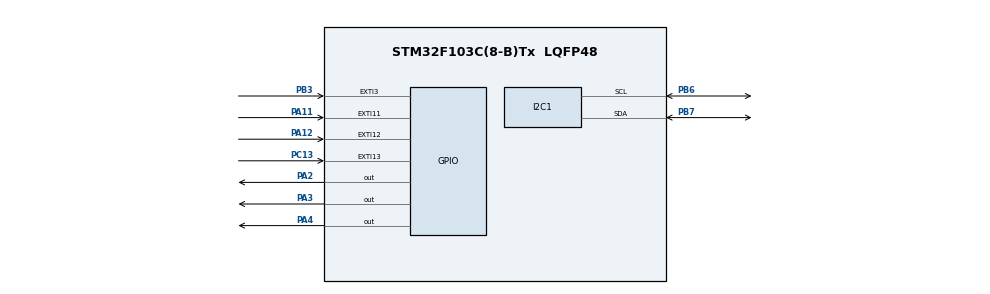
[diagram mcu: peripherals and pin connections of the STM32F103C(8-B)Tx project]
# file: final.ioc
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Mcu.Family=STM32F1
Mcu.Name=STM32F103C(8-B)Tx
Mcu.Package=LQFP48
NVIC.EXTI15_10_IRQn=true\:0\:0\:false\:false\:true\:true\:true\:true
NVIC.EXTI3_IRQn=true\:0\:0\:false\:false\:true\:true\:true\:true
NVIC.PriorityGroup=NVIC_PRIORITYGROUP_4
NVIC.TIM1_CC_IRQn=true\:0\:0\:false\:false\:true\:true\:true\:true
PA11.GPIO_ModeDefaultEXTI=GPIO_MODE_IT_RISING
PA11.Signal=GPXTI11
PA12.GPIO_ModeDefaultEXTI=GPIO_MODE_IT_FALLING
PA12.Signal=GPXTI12
PA2.Signal=GPIO_Output
PA3.Signal=GPIO_Output
PA4.Signal=GPIO_Output
PB3.GPIO_ModeDefaultEXTI=GPIO_MODE_IT_FALLING
PB3.Signal=GPXTI3
PB6.Mode=I2C
PB6.Signal=I2C1_SCL
PB7.Mode=I2C
PB7.Signal=I2C1_SDA
PC13-TAMPER-RTC.Signal=GPXTI13
ProjectManager.HeapSize=0x200
ProjectManager.StackSize=0x400
ProjectManager.TargetToolchain=STM32CubeIDE
RCC.APB1Freq_Value=8000000
RCC.APB2Freq_Value=8000000
VP_SYS_VS_ND.Mode=No_Debug
VP_TIM1_VS_ClockSourceINT.Mode=Internal
VP_TIM1_VS_ClockSourceITR.Mode=TriggerSource_ITR0
board=custom

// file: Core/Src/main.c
/* USER CODE BEGIN Header */
/**
  ******************************************************************************
  * @file           : main.c
  * @brief          : Main program body
  ******************************************************************************
  * @attention
  *
  * Copyright (c) 2023 STMicroelectronics.
  * All rights reserved.
  *
  * This software is licensed under terms that can be found in the LICENSE file
  * in the root directory of this software component.
  * If no LICENSE file comes with this software, it is provided AS-IS.
  *
  ******************************************************************************
  */
/* USER CODE END Header */
#include "main.h"
#include "button.h"
#include "CLCD_I2C.h"
#include "mpu_ss.h"

I2C_HandleTypeDef hi2c1;
CLCD_I2C_Name lcd;
TIM_HandleTypeDef htim1;

int step = -1;
double pre = 0;
int c = 0;
void SystemClock_Config(void);
static void MX_GPIO_Init(void);
static void MX_I2C1_Init(void);
static void MX_TIM1_Init(void);

int main(void)
{
  /* USER CODE BEGIN 1 */
	char buf[8];
  /* USER CODE END 1 */

  /* MCU Configuration--------------------------------------------------------*/

  /* Reset of all peripherals, Initializes the Flash interface and the Systick. */
  HAL_Init();

  /* Configure the system clock */
  SystemClock_Config();

  /* USER CODE BEGIN SysInit */
  init_button();
  /* USER CODE END SysInit */

  /* Initialize all configured peripherals */
  MX_GPIO_Init();
  MX_I2C1_Init();
  MX_TIM1_Init();
  /* USER CODE BEGIN 2 */
  MPU6050_Init(&hi2c1);
  CLCD_I2C_Init(&lcd, &hi2c1, 0x27 << 1, 16, 2);
  CLCD_I2C_Clear(&lcd);
  CLCD_I2C_CursorOn(&lcd);
  /* USER CODE END 2 */

  /* Infinite loop */
  while (1)
  {
	 CLCD_I2C_Clear(&lcd);
	 double vec = MPUgetValue(&hi2c1);
	 if(check(PIN_RESET) == 0u) {
		 step = 0;
		 CLCD_I2C_SetCursor(&lcd, 0, 0);
		 CLCD_I2C_WriteString(&lcd, "STEP: ");
		 sprintf(buf, "%d", step);
		 CLCD_I2C_WriteString(&lcd, buf);
		 HAL_Delay(200);
	 } else {
		 if(check(PIN_PAUSE) == 0u) {
			 HAL_Delay(100);
			 while(check(PIN_PAUSE) == 0u) {

			 }
		 } else {
			 if(vec - pre > 4000) {
				 step++;
			 }
		 }
	 }
	 CLCD_I2C_SetCursor(&lcd, 0, 0);
	 CLCD_I2C_WriteString(&lcd, "STEP: ");
	 sprintf(buf, "%d", vec - pre);
	 CLCD_I2C_WriteString(&lcd, buf);
	 pre = vec;
	 HAL_Delay(100);

  }
}

void SystemClock_Config(void)
{
  RCC_OscInitTypeDef RCC_OscInitStruct = {0};
  RCC_ClkInitTypeDef RCC_ClkInitStruct = {0};

  /** Initializes the RCC Oscillators according to the specified parameters
  * in the RCC_OscInitTypeDef structure.
  */
  RCC_OscInitStruct.OscillatorType = RCC_OSCILLATORTYPE_HSI;
  RCC_OscInitStruct.HSIState = RCC_HSI_ON;
  RCC_OscInitStruct.HSICalibrationValue = RCC_HSICALIBRATION_DEFAULT;
  RCC_OscInitStruct.PLL.PLLState = RCC_PLL_NONE;
  if (HAL_RCC_OscConfig(&RCC_OscInitStruct) != HAL_OK)
  {
    Error_Handler();
  }

  /** Initializes the CPU, AHB and APB buses clocks
  */
  RCC_ClkInitStruct.ClockType = RCC_CLOCKTYPE_HCLK|RCC_CLOCKTYPE_SYSCLK
                              |RCC_CLOCKTYPE_PCLK1|RCC_CLOCKTYPE_PCLK2;
  RCC_ClkInitStruct.SYSCLKSource = RCC_SYSCLKSOURCE_HSI;
  RCC_ClkInitStruct.AHBCLKDivider = RCC_SYSCLK_DIV1;
  RCC_ClkInitStruct.APB1CLKDivider = RCC_HCLK_DIV1;
  RCC_ClkInitStruct.APB2CLKDivider = RCC_HCLK_DIV1;

  if (HAL_RCC_ClockConfig(&RCC_ClkInitStruct, FLASH_LATENCY_0) != HAL_OK)
  {
    Error_Handler();
  }
}

static void MX_I2C1_Init(void)
{

  hi2c1.Instance = I2C1;
  hi2c1.Init.ClockSpeed = 100000;
  hi2c1.Init.DutyCycle = I2C_DUTYCYCLE_2;
  hi2c1.Init.OwnAddress1 = 0;
  hi2c1.Init.AddressingMode = I2C_ADDRESSINGMODE_7BIT;
  hi2c1.Init.DualAddressMode = I2C_DUALADDRESS_DISABLE;
  hi2c1.Init.OwnAddress2 = 0;
  hi2c1.Init.GeneralCallMode = I2C_GENERALCALL_DISABLE;
  hi2c1.Init.NoStretchMode = I2C_NOSTRETCH_DISABLE;
  if (HAL_I2C_Init(&hi2c1) != HAL_OK)
  {
    Error_Handler();
  }

}

static void MX_TIM1_Init(void)
{

  TIM_ClockConfigTypeDef sClockSourceConfig = {0};
  TIM_SlaveConfigTypeDef sSlaveConfig = {0};
  TIM_MasterConfigTypeDef sMasterConfig = {0};

  htim1.Instance = TIM1;
  htim1.Init.Prescaler = 0;
  htim1.Init.CounterMode = TIM_COUNTERMODE_UP;
  htim1.Init.Period = 65535;
  htim1.Init.ClockDivision = TIM_CLOCKDIVISION_DIV1;
  htim1.Init.RepetitionCounter = 0;
  htim1.Init.AutoReloadPreload = TIM_AUTORELOAD_PRELOAD_DISABLE;
  if (HAL_TIM_Base_Init(&htim1) != HAL_OK)
  {
    Error_Handler();
  }
  sClockSourceConfig.ClockSource = TIM_CLOCKSOURCE_INTERNAL;
  if (HAL_TIM_ConfigClockSource(&htim1, &sClockSourceConfig) != HAL_OK)
  {
    Error_Handler();
  }
  sSlaveConfig.SlaveMode = TIM_SLAVEMODE_DISABLE;
  sSlaveConfig.InputTrigger = TIM_TS_ITR0;
  if (HAL_TIM_SlaveConfigSynchro(&htim1, &sSlaveConfig) != HAL_OK)
  {
    Error_Handler();
  }
  sMasterConfig.MasterOutputTrigger = TIM_TRGO_RESET;
  sMasterConfig.MasterSlaveMode = TIM_MASTERSLAVEMODE_DISABLE;
  if (HAL_TIMEx_MasterConfigSynchronization(&htim1, &sMasterConfig) != HAL_OK)
  {
    Error_Handler();
  }

}

static void MX_GPIO_Init(void)
{
  GPIO_InitTypeDef GPIO_InitStruct = {0};

  /* GPIO Ports Clock Enable */
  __HAL_RCC_GPIOC_CLK_ENABLE();
  __HAL_RCC_GPIOA_CLK_ENABLE();
  __HAL_RCC_GPIOB_CLK_ENABLE();

  /*Configure GPIO pin Output Level */
  HAL_GPIO_WritePin(GPIOB, GPIO_PIN_5, GPIO_PIN_RESET);

  /*Configure GPIO pin : PC13 */
  GPIO_InitStruct.Pin = GPIO_PIN_13;
  GPIO_InitStruct.Mode = GPIO_MODE_IT_RISING;
  GPIO_InitStruct.Pull = GPIO_NOPULL;
  HAL_GPIO_Init(GPIOC, &GPIO_InitStruct);

  /*Configure GPIO pin : PA0 */
  GPIO_InitStruct.Pin = GPIO_PIN_0;
  GPIO_InitStruct.Mode = GPIO_MODE_IT_RISING;
  GPIO_InitStruct.Pull = GPIO_NOPULL;
  HAL_GPIO_Init(GPIOA, &GPIO_InitStruct);

  /*Configure GPIO pin : PA12 */
  GPIO_InitStruct.Pin = GPIO_PIN_12;
  GPIO_InitStruct.Mode = GPIO_MODE_IT_FALLING;
  GPIO_InitStruct.Pull = GPIO_NOPULL;
  HAL_GPIO_Init(GPIOA, &GPIO_InitStruct);

  /*Configure GPIO pin : PB3 */
  GPIO_InitStruct.Pin = GPIO_PIN_3;
  GPIO_InitStruct.Mode = GPIO_MODE_IT_FALLING;
  GPIO_InitStruct.Pull = GPIO_NOPULL;
  HAL_GPIO_Init(GPIOB, &GPIO_InitStruct);

  /*Configure GPIO pin : PB5 */
  GPIO_InitStruct.Pin = GPIO_PIN_5;
  GPIO_InitStruct.Mode = GPIO_MODE_OUTPUT_PP;
  GPIO_InitStruct.Pull = GPIO_NOPULL;
  GPIO_InitStruct.Speed = GPIO_SPEED_FREQ_LOW;
  HAL_GPIO_Init(GPIOB, &GPIO_InitStruct);

  /* EXTI interrupt init*/
  HAL_NVIC_SetPriority(EXTI0_IRQn, 0, 0);
  HAL_NVIC_EnableIRQ(EXTI0_IRQn);

  HAL_NVIC_SetPriority(EXTI3_IRQn, 0, 0);
  HAL_NVIC_EnableIRQ(EXTI3_IRQn);

  HAL_NVIC_SetPriority(EXTI15_10_IRQn, 0, 0);
  HAL_NVIC_EnableIRQ(EXTI15_10_IRQn);

}

void Error_Handler(void)
{
  __disable_irq();
  while (1)
  {
  }
}
